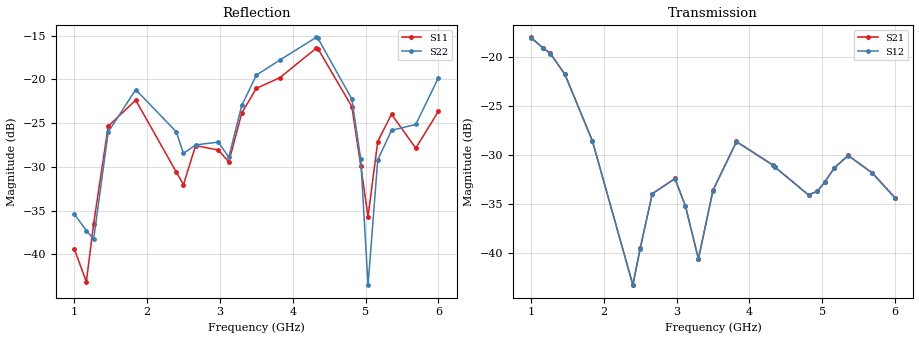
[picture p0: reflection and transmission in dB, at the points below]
!Agilent Technologies,E8364B,MY43040528,A.07.50.67
!Agilent E8364B: A.07.50.67
!Date: Sunday, March 01, 2026 20:59:48
!Correction: S11(Full 2 Port(1,2))
!S21(Full 2 Port(1,2))
!S12(Full 2 Port(1,2))
!S22(Full 2 Port(1,2))
!S2P File: Measurements: S11, S21, S12, S22:
# Hz S  dB  R 50
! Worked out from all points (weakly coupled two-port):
!   451 points, 1 GHz to 6 GHz, reference 50 ohm
!   highest |S21| = -17.97 dB at 1 GHz (marker M1); lowest = -43.3 dB at 2.4 GHz (marker M2)
!   lowest |S11| = -43.1 dB at 1.167 GHz (marker M3), VSWR 1.01, Z = 49.5 + j0.49 ohm
!   |S11| at or under -10 dB: start of sweep to end of sweep
!   |S22| runs from -43.5 to -15.0 dB; largest |S21 - S12| = 0.0004
!   S11 on the Smith chart (normalised r, x): 1 GHz: 1.01, +0.02; 4.322 GHz: 1.24, -0.24; 6 GHz: 0.99, -0.13
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1e9  -39.34 64.8  -17.97 25.5  -18.00 25.5  -35.37 10.5
1.166667e9  -43.12 134.9  -19.05 -24.5  -19.07 -24.6  -37.26 34.7
1.266667e9  -36.50 -174.9  -19.60 -57.1  -19.63 -57.1  -38.26 76.3
1.466667e9  -25.35 161.8  -21.74 -125.1  -21.76 -125.1  -26.01 73.8
1.844444e9  -22.36 93.8  -28.56 115.9  -28.58 115.9  -21.16 -9.8
2.4e9  -30.56 50.4  -43.31 -130.8  -43.34 -131.0  -25.97 -92.7
2.5e9  -32.02 71.1  -39.58 145.4  -39.63 145.4  -28.45 -91.3
2.666667e9  -27.55 83.0  -33.97 59.1  -34.00 59.1  -27.48 -77.2
2.977778e9  -28.07 49.3  -32.42 -69.5  -32.45 -69.5  -27.15 -112.2
3.122222e9  -29.42 72.6  -35.24 -119.7  -35.27 -119.7  -28.89 -94.8
3.3e9  -23.83 76.4  -40.64 -133.9  -40.68 -133.9  -22.97 -91.7
3.5e9  -21.02 50.5  -33.62 -154.9  -33.65 -154.9  -19.51 -123.8
3.822222e9  -19.80 26.3  -28.63 87.2  -28.66 87.2  -17.78 -163.5
4.322222e9  -16.43 -38.8  -31.03 -94.2  -31.07 -94.1  -15.19 112.0
4.344444e9  -16.46 -42.2  -31.21 -102.0  -31.23 -102.0  -15.28 107.5
4.811111e9  -23.10 -119.2  -34.09 54.2  -34.12 54.2  -22.23 6.9
4.933333e9  -29.85 -128.0  -33.72 -15.2  -33.75 -15.1  -29.12 -19.6
5.033333e9  -35.67 -72.3  -32.78 -70.9  -32.81 -70.9  -43.50 32.6
5.166667e9  -27.09 -49.6  -31.31 -139.7  -31.35 -139.7  -29.20 79.4
5.355556e9  -23.97 -79.1  -30.05 132.5  -30.08 132.5  -25.81 43.4
5.688889e9  -27.85 -90.0  -31.85 -1.4  -31.89 -1.4  -25.14 38.1
6e9  -23.63 -90.7  -34.40 -84.4  -34.44 -84.4  -19.79 0.0
